One B-rep face of a CAD part: STEP entity #137.
In plain terms, the planar face has unit normal (-1, 0, 0).
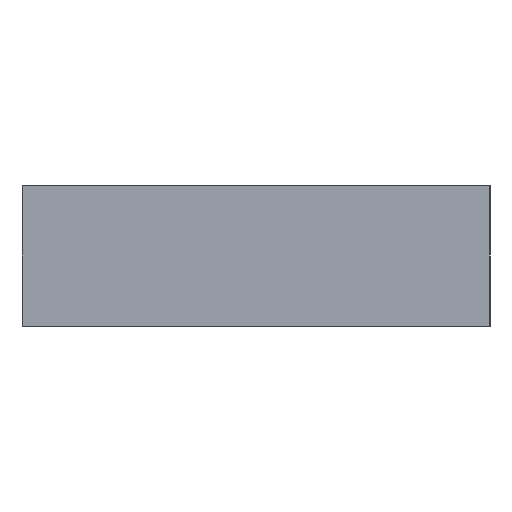
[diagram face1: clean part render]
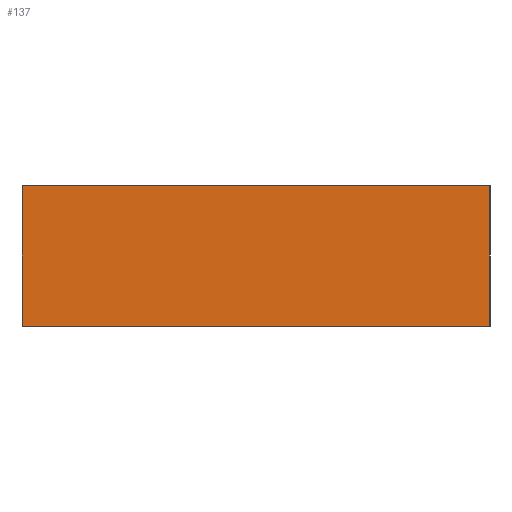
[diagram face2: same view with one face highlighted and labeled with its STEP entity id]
Its self-contained STEP definition (entity closure, numbers rounded to 3 decimals):
#32 = PLANE('',#33);
#33 = AXIS2_PLACEMENT_3D('',#34,#35,#36);
#34 = CARTESIAN_POINT('',(100.,-10.,0.));
#35 = DIRECTION('',(-0.,1.,-0.));
#36 = DIRECTION('',(1.,0.,0.));
#57 = VERTEX_POINT('',#58);
#58 = CARTESIAN_POINT('',(-100.,-10.,6.));
#72 = PLANE('',#73);
#73 = AXIS2_PLACEMENT_3D('',#74,#75,#76);
#74 = CARTESIAN_POINT('',(0.,0.,6.));
#75 = DIRECTION('',(-0.,-0.,1.));
#76 = DIRECTION('',(1.,0.,0.));
#84 = EDGE_CURVE('',#85,#57,#87,.T.);
#85 = VERTEX_POINT('',#86);
#86 = CARTESIAN_POINT('',(-100.,-10.,0.));
#87 = SURFACE_CURVE('',#88,(#92,#99),.PCURVE_S1.);
#88 = LINE('',#89,#90);
#89 = CARTESIAN_POINT('',(-100.,-10.,0.));
#90 = VECTOR('',#91,1.);
#91 = DIRECTION('',(-0.,-0.,1.));
#92 = PCURVE('',#32,#93);
#93 = DEFINITIONAL_REPRESENTATION('',(#94),#98);
#94 = LINE('',#95,#96);
#95 = CARTESIAN_POINT('',(-200.,0.));
#96 = VECTOR('',#97,1.);
#97 = DIRECTION('',(-0.,-1.));
#98 = ( GEOMETRIC_REPRESENTATION_CONTEXT(2) 
PARAMETRIC_REPRESENTATION_CONTEXT() REPRESENTATION_CONTEXT('2D SPACE',''
  ) );
#99 = PCURVE('',#100,#105);
#100 = PLANE('',#101);
#101 = AXIS2_PLACEMENT_3D('',#102,#103,#104);
#102 = CARTESIAN_POINT('',(-100.,-10.,0.));
#103 = DIRECTION('',(1.,-0.,-0.));
#104 = DIRECTION('',(0.,-1.,0.));
#105 = DEFINITIONAL_REPRESENTATION('',(#106),#110);
#106 = LINE('',#107,#108);
#107 = CARTESIAN_POINT('',(-0.,-0.));
#108 = VECTOR('',#109,1.);
#109 = DIRECTION('',(-0.,-1.));
#110 = ( GEOMETRIC_REPRESENTATION_CONTEXT(2) 
PARAMETRIC_REPRESENTATION_CONTEXT() REPRESENTATION_CONTEXT('2D SPACE',''
  ) );
#126 = PLANE('',#127);
#127 = AXIS2_PLACEMENT_3D('',#128,#129,#130);
#128 = CARTESIAN_POINT('',(0.,0.,0.));
#129 = DIRECTION('',(-0.,-0.,1.));
#130 = DIRECTION('',(1.,0.,0.));
#137 = ADVANCED_FACE('',(#138),#100,.F.);
#138 = FACE_BOUND('',#139,.T.);
#139 = EDGE_LOOP('',(#140,#141,#164,#192));
#140 = ORIENTED_EDGE('',*,*,#84,.T.);
#141 = ORIENTED_EDGE('',*,*,#142,.T.);
#142 = EDGE_CURVE('',#57,#143,#145,.T.);
#143 = VERTEX_POINT('',#144);
#144 = CARTESIAN_POINT('',(-100.,10.,6.));
#145 = SURFACE_CURVE('',#146,(#150,#157),.PCURVE_S1.);
#146 = LINE('',#147,#148);
#147 = CARTESIAN_POINT('',(-100.,-10.,6.));
#148 = VECTOR('',#149,1.);
#149 = DIRECTION('',(-0.,1.,-0.));
#150 = PCURVE('',#100,#151);
#151 = DEFINITIONAL_REPRESENTATION('',(#152),#156);
#152 = LINE('',#153,#154);
#153 = CARTESIAN_POINT('',(-0.,-6.));
#154 = VECTOR('',#155,1.);
#155 = DIRECTION('',(-1.,0.));
#156 = ( GEOMETRIC_REPRESENTATION_CONTEXT(2) 
PARAMETRIC_REPRESENTATION_CONTEXT() REPRESENTATION_CONTEXT('2D SPACE',''
  ) );
#157 = PCURVE('',#72,#158);
#158 = DEFINITIONAL_REPRESENTATION('',(#159),#163);
#159 = LINE('',#160,#161);
#160 = CARTESIAN_POINT('',(-100.,-10.));
#161 = VECTOR('',#162,1.);
#162 = DIRECTION('',(-0.,1.));
#163 = ( GEOMETRIC_REPRESENTATION_CONTEXT(2) 
PARAMETRIC_REPRESENTATION_CONTEXT() REPRESENTATION_CONTEXT('2D SPACE',''
  ) );
#164 = ORIENTED_EDGE('',*,*,#165,.F.);
#165 = EDGE_CURVE('',#166,#143,#168,.T.);
#166 = VERTEX_POINT('',#167);
#167 = CARTESIAN_POINT('',(-100.,10.,0.));
#168 = SURFACE_CURVE('',#169,(#173,#180),.PCURVE_S1.);
#169 = LINE('',#170,#171);
#170 = CARTESIAN_POINT('',(-100.,10.,0.));
#171 = VECTOR('',#172,1.);
#172 = DIRECTION('',(-0.,-0.,1.));
#173 = PCURVE('',#100,#174);
#174 = DEFINITIONAL_REPRESENTATION('',(#175),#179);
#175 = LINE('',#176,#177);
#176 = CARTESIAN_POINT('',(-20.,-0.));
#177 = VECTOR('',#178,1.);
#178 = DIRECTION('',(-0.,-1.));
#179 = ( GEOMETRIC_REPRESENTATION_CONTEXT(2) 
PARAMETRIC_REPRESENTATION_CONTEXT() REPRESENTATION_CONTEXT('2D SPACE',''
  ) );
#180 = PCURVE('',#181,#186);
#181 = PLANE('',#182);
#182 = AXIS2_PLACEMENT_3D('',#183,#184,#185);
#183 = CARTESIAN_POINT('',(-100.,10.,0.));
#184 = DIRECTION('',(-0.,-1.,-0.));
#185 = DIRECTION('',(-1.,0.,0.));
#186 = DEFINITIONAL_REPRESENTATION('',(#187),#191);
#187 = LINE('',#188,#189);
#188 = CARTESIAN_POINT('',(-0.,0.));
#189 = VECTOR('',#190,1.);
#190 = DIRECTION('',(-0.,-1.));
#191 = ( GEOMETRIC_REPRESENTATION_CONTEXT(2) 
PARAMETRIC_REPRESENTATION_CONTEXT() REPRESENTATION_CONTEXT('2D SPACE',''
  ) );
#192 = ORIENTED_EDGE('',*,*,#193,.F.);
#193 = EDGE_CURVE('',#85,#166,#194,.T.);
#194 = SURFACE_CURVE('',#195,(#199,#206),.PCURVE_S1.);
#195 = LINE('',#196,#197);
#196 = CARTESIAN_POINT('',(-100.,-10.,0.));
#197 = VECTOR('',#198,1.);
#198 = DIRECTION('',(-0.,1.,-0.));
#199 = PCURVE('',#100,#200);
#200 = DEFINITIONAL_REPRESENTATION('',(#201),#205);
#201 = LINE('',#202,#203);
#202 = CARTESIAN_POINT('',(-0.,-0.));
#203 = VECTOR('',#204,1.);
#204 = DIRECTION('',(-1.,0.));
#205 = ( GEOMETRIC_REPRESENTATION_CONTEXT(2) 
PARAMETRIC_REPRESENTATION_CONTEXT() REPRESENTATION_CONTEXT('2D SPACE',''
  ) );
#206 = PCURVE('',#126,#207);
#207 = DEFINITIONAL_REPRESENTATION('',(#208),#212);
#208 = LINE('',#209,#210);
#209 = CARTESIAN_POINT('',(-100.,-10.));
#210 = VECTOR('',#211,1.);
#211 = DIRECTION('',(-0.,1.));
#212 = ( GEOMETRIC_REPRESENTATION_CONTEXT(2) 
PARAMETRIC_REPRESENTATION_CONTEXT() REPRESENTATION_CONTEXT('2D SPACE',''
  ) );
